VERSION 5.7 ;
BUSBITCHARS "[]" ;
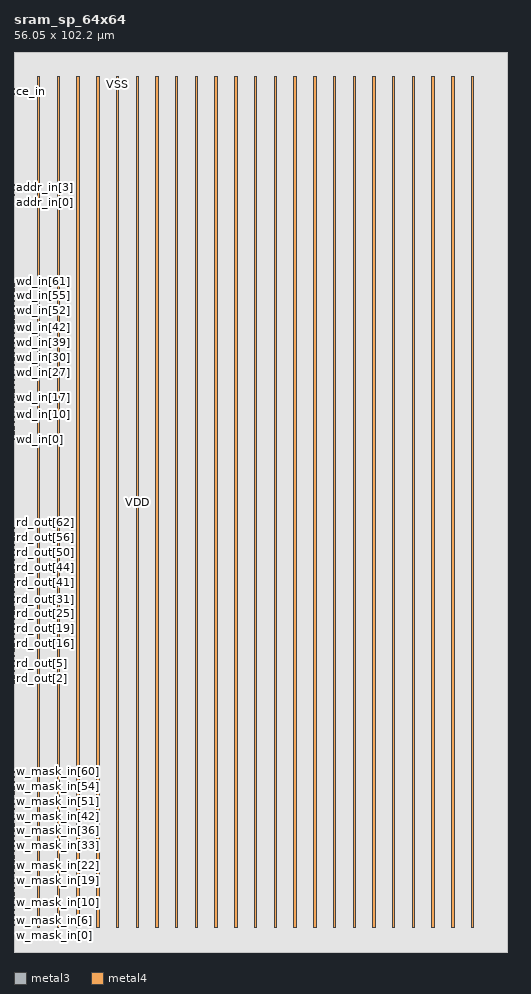
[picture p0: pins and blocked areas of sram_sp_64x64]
MACRO sram_sp_64x64
  FOREIGN sram_sp_64x64 0 0 ;
  SYMMETRY X Y R90 ;
  SIZE 56.050 BY 102.200 ;
  CLASS BLOCK ;
  PIN w_mask_in[0]
    DIRECTION INPUT ;
    USE SIGNAL ;
    SHAPE ABUTMENT ;
    PORT
      LAYER metal3 ;
      RECT 0.000 2.765 0.070 2.835 ;
    END
  END w_mask_in[0]
  PIN w_mask_in[1]
    DIRECTION INPUT ;
    USE SIGNAL ;
    SHAPE ABUTMENT ;
    PORT
      LAYER metal3 ;
      RECT 0.000 3.045 0.070 3.115 ;
    END
  END w_mask_in[1]
  PIN w_mask_in[2]
    DIRECTION INPUT ;
    USE SIGNAL ;
    SHAPE ABUTMENT ;
    PORT
      LAYER metal3 ;
      RECT 0.000 3.325 0.070 3.395 ;
    END
  END w_mask_in[2]
  PIN w_mask_in[3]
    DIRECTION INPUT ;
    USE SIGNAL ;
    SHAPE ABUTMENT ;
    PORT
      LAYER metal3 ;
      RECT 0.000 3.605 0.070 3.675 ;
    END
  END w_mask_in[3]
  PIN w_mask_in[4]
    DIRECTION INPUT ;
    USE SIGNAL ;
    SHAPE ABUTMENT ;
    PORT
      LAYER metal3 ;
      RECT 0.000 3.885 0.070 3.955 ;
    END
  END w_mask_in[4]
  PIN w_mask_in[5]
    DIRECTION INPUT ;
    USE SIGNAL ;
    SHAPE ABUTMENT ;
    PORT
      LAYER metal3 ;
      RECT 0.000 4.165 0.070 4.235 ;
    END
  END w_mask_in[5]
  PIN w_mask_in[6]
    DIRECTION INPUT ;
    USE SIGNAL ;
    SHAPE ABUTMENT ;
    PORT
      LAYER metal3 ;
      RECT 0.000 4.445 0.070 4.515 ;
    END
  END w_mask_in[6]
  PIN w_mask_in[7]
    DIRECTION INPUT ;
    USE SIGNAL ;
    SHAPE ABUTMENT ;
    PORT
      LAYER metal3 ;
      RECT 0.000 4.725 0.070 4.795 ;
    END
  END w_mask_in[7]
  PIN w_mask_in[8]
    DIRECTION INPUT ;
    USE SIGNAL ;
    SHAPE ABUTMENT ;
    PORT
      LAYER metal3 ;
      RECT 0.000 5.005 0.070 5.075 ;
    END
  END w_mask_in[8]
  PIN w_mask_in[9]
    DIRECTION INPUT ;
    USE SIGNAL ;
    SHAPE ABUTMENT ;
    PORT
      LAYER metal3 ;
      RECT 0.000 5.285 0.070 5.355 ;
    END
  END w_mask_in[9]
  PIN w_mask_in[10]
    DIRECTION INPUT ;
    USE SIGNAL ;
    SHAPE ABUTMENT ;
    PORT
      LAYER metal3 ;
      RECT 0.000 5.565 0.070 5.635 ;
    END
  END w_mask_in[10]
  PIN w_mask_in[11]
    DIRECTION INPUT ;
    USE SIGNAL ;
    SHAPE ABUTMENT ;
    PORT
      LAYER metal3 ;
      RECT 0.000 5.845 0.070 5.915 ;
    END
  END w_mask_in[11]
  PIN w_mask_in[12]
    DIRECTION INPUT ;
    USE SIGNAL ;
    SHAPE ABUTMENT ;
    PORT
      LAYER metal3 ;
      RECT 0.000 6.125 0.070 6.195 ;
    END
  END w_mask_in[12]
  PIN w_mask_in[13]
    DIRECTION INPUT ;
    USE SIGNAL ;
    SHAPE ABUTMENT ;
    PORT
      LAYER metal3 ;
      RECT 0.000 6.405 0.070 6.475 ;
    END
  END w_mask_in[13]
  PIN w_mask_in[14]
    DIRECTION INPUT ;
    USE SIGNAL ;
    SHAPE ABUTMENT ;
    PORT
      LAYER metal3 ;
      RECT 0.000 6.685 0.070 6.755 ;
    END
  END w_mask_in[14]
  PIN w_mask_in[15]
    DIRECTION INPUT ;
    USE SIGNAL ;
    SHAPE ABUTMENT ;
    PORT
      LAYER metal3 ;
      RECT 0.000 6.965 0.070 7.035 ;
    END
  END w_mask_in[15]
  PIN w_mask_in[16]
    DIRECTION INPUT ;
    USE SIGNAL ;
    SHAPE ABUTMENT ;
    PORT
      LAYER metal3 ;
      RECT 0.000 7.245 0.070 7.315 ;
    END
  END w_mask_in[16]
  PIN w_mask_in[17]
    DIRECTION INPUT ;
    USE SIGNAL ;
    SHAPE ABUTMENT ;
    PORT
      LAYER metal3 ;
      RECT 0.000 7.525 0.070 7.595 ;
    END
  END w_mask_in[17]
  PIN w_mask_in[18]
    DIRECTION INPUT ;
    USE SIGNAL ;
    SHAPE ABUTMENT ;
    PORT
      LAYER metal3 ;
      RECT 0.000 7.805 0.070 7.875 ;
    END
  END w_mask_in[18]
  PIN w_mask_in[19]
    DIRECTION INPUT ;
    USE SIGNAL ;
    SHAPE ABUTMENT ;
    PORT
      LAYER metal3 ;
      RECT 0.000 8.085 0.070 8.155 ;
    END
  END w_mask_in[19]
  PIN w_mask_in[20]
    DIRECTION INPUT ;
    USE SIGNAL ;
    SHAPE ABUTMENT ;
    PORT
      LAYER metal3 ;
      RECT 0.000 8.365 0.070 8.435 ;
    END
  END w_mask_in[20]
  PIN w_mask_in[21]
    DIRECTION INPUT ;
    USE SIGNAL ;
    SHAPE ABUTMENT ;
    PORT
      LAYER metal3 ;
      RECT 0.000 8.645 0.070 8.715 ;
    END
  END w_mask_in[21]
  PIN w_mask_in[22]
    DIRECTION INPUT ;
    USE SIGNAL ;
    SHAPE ABUTMENT ;
    PORT
      LAYER metal3 ;
      RECT 0.000 8.925 0.070 8.995 ;
    END
  END w_mask_in[22]
  PIN w_mask_in[23]
    DIRECTION INPUT ;
    USE SIGNAL ;
    SHAPE ABUTMENT ;
    PORT
      LAYER metal3 ;
      RECT 0.000 9.205 0.070 9.275 ;
    END
  END w_mask_in[23]
  PIN w_mask_in[24]
    DIRECTION INPUT ;
    USE SIGNAL ;
    SHAPE ABUTMENT ;
    PORT
      LAYER metal3 ;
      RECT 0.000 9.485 0.070 9.555 ;
    END
  END w_mask_in[24]
  PIN w_mask_in[25]
    DIRECTION INPUT ;
    USE SIGNAL ;
    SHAPE ABUTMENT ;
    PORT
      LAYER metal3 ;
      RECT 0.000 9.765 0.070 9.835 ;
    END
  END w_mask_in[25]
  PIN w_mask_in[26]
    DIRECTION INPUT ;
    USE SIGNAL ;
    SHAPE ABUTMENT ;
    PORT
      LAYER metal3 ;
      RECT 0.000 10.045 0.070 10.115 ;
    END
  END w_mask_in[26]
  PIN w_mask_in[27]
    DIRECTION INPUT ;
    USE SIGNAL ;
    SHAPE ABUTMENT ;
    PORT
      LAYER metal3 ;
      RECT 0.000 10.325 0.070 10.395 ;
    END
  END w_mask_in[27]
  PIN w_mask_in[28]
    DIRECTION INPUT ;
    USE SIGNAL ;
    SHAPE ABUTMENT ;
    PORT
      LAYER metal3 ;
      RECT 0.000 10.605 0.070 10.675 ;
    END
  END w_mask_in[28]
  PIN w_mask_in[29]
    DIRECTION INPUT ;
    USE SIGNAL ;
    SHAPE ABUTMENT ;
    PORT
      LAYER metal3 ;
      RECT 0.000 10.885 0.070 10.955 ;
    END
  END w_mask_in[29]
  PIN w_mask_in[30]
    DIRECTION INPUT ;
    USE SIGNAL ;
    SHAPE ABUTMENT ;
    PORT
      LAYER metal3 ;
      RECT 0.000 11.165 0.070 11.235 ;
    END
  END w_mask_in[30]
  PIN w_mask_in[31]
    DIRECTION INPUT ;
    USE SIGNAL ;
    SHAPE ABUTMENT ;
    PORT
      LAYER metal3 ;
      RECT 0.000 11.445 0.070 11.515 ;
    END
  END w_mask_in[31]
  PIN w_mask_in[32]
    DIRECTION INPUT ;
    USE SIGNAL ;
    SHAPE ABUTMENT ;
    PORT
      LAYER metal3 ;
      RECT 0.000 11.725 0.070 11.795 ;
    END
  END w_mask_in[32]
  PIN w_mask_in[33]
    DIRECTION INPUT ;
    USE SIGNAL ;
    SHAPE ABUTMENT ;
    PORT
      LAYER metal3 ;
      RECT 0.000 12.005 0.070 12.075 ;
    END
  END w_mask_in[33]
  PIN w_mask_in[34]
    DIRECTION INPUT ;
    USE SIGNAL ;
    SHAPE ABUTMENT ;
    PORT
      LAYER metal3 ;
      RECT 0.000 12.285 0.070 12.355 ;
    END
  END w_mask_in[34]
  PIN w_mask_in[35]
    DIRECTION INPUT ;
    USE SIGNAL ;
    SHAPE ABUTMENT ;
    PORT
      LAYER metal3 ;
      RECT 0.000 12.565 0.070 12.635 ;
    END
  END w_mask_in[35]
  PIN w_mask_in[36]
    DIRECTION INPUT ;
    USE SIGNAL ;
    SHAPE ABUTMENT ;
    PORT
      LAYER metal3 ;
      RECT 0.000 12.845 0.070 12.915 ;
    END
  END w_mask_in[36]
  PIN w_mask_in[37]
    DIRECTION INPUT ;
    USE SIGNAL ;
    SHAPE ABUTMENT ;
    PORT
      LAYER metal3 ;
      RECT 0.000 13.125 0.070 13.195 ;
    END
  END w_mask_in[37]
  PIN w_mask_in[38]
    DIRECTION INPUT ;
    USE SIGNAL ;
    SHAPE ABUTMENT ;
    PORT
      LAYER metal3 ;
      RECT 0.000 13.405 0.070 13.475 ;
    END
  END w_mask_in[38]
  PIN w_mask_in[39]
    DIRECTION INPUT ;
    USE SIGNAL ;
    SHAPE ABUTMENT ;
    PORT
      LAYER metal3 ;
      RECT 0.000 13.685 0.070 13.755 ;
    END
  END w_mask_in[39]
  PIN w_mask_in[40]
    DIRECTION INPUT ;
    USE SIGNAL ;
    SHAPE ABUTMENT ;
    PORT
      LAYER metal3 ;
      RECT 0.000 13.965 0.070 14.035 ;
    END
  END w_mask_in[40]
  PIN w_mask_in[41]
    DIRECTION INPUT ;
    USE SIGNAL ;
    SHAPE ABUTMENT ;
    PORT
      LAYER metal3 ;
      RECT 0.000 14.245 0.070 14.315 ;
    END
  END w_mask_in[41]
  PIN w_mask_in[42]
    DIRECTION INPUT ;
    USE SIGNAL ;
    SHAPE ABUTMENT ;
    PORT
      LAYER metal3 ;
      RECT 0.000 14.525 0.070 14.595 ;
    END
  END w_mask_in[42]
  PIN w_mask_in[43]
    DIRECTION INPUT ;
    USE SIGNAL ;
    SHAPE ABUTMENT ;
    PORT
      LAYER metal3 ;
      RECT 0.000 14.805 0.070 14.875 ;
    END
  END w_mask_in[43]
  PIN w_mask_in[44]
    DIRECTION INPUT ;
    USE SIGNAL ;
    SHAPE ABUTMENT ;
    PORT
      LAYER metal3 ;
      RECT 0.000 15.085 0.070 15.155 ;
    END
  END w_mask_in[44]
  PIN w_mask_in[45]
    DIRECTION INPUT ;
    USE SIGNAL ;
    SHAPE ABUTMENT ;
    PORT
      LAYER metal3 ;
      RECT 0.000 15.365 0.070 15.435 ;
    END
  END w_mask_in[45]
  PIN w_mask_in[46]
    DIRECTION INPUT ;
    USE SIGNAL ;
    SHAPE ABUTMENT ;
    PORT
      LAYER metal3 ;
      RECT 0.000 15.645 0.070 15.715 ;
    END
  END w_mask_in[46]
  PIN w_mask_in[47]
    DIRECTION INPUT ;
    USE SIGNAL ;
    SHAPE ABUTMENT ;
    PORT
      LAYER metal3 ;
      RECT 0.000 15.925 0.070 15.995 ;
    END
  END w_mask_in[47]
  PIN w_mask_in[48]
    DIRECTION INPUT ;
    USE SIGNAL ;
    SHAPE ABUTMENT ;
    PORT
      LAYER metal3 ;
      RECT 0.000 16.205 0.070 16.275 ;
    END
  END w_mask_in[48]
  PIN w_mask_in[49]
    DIRECTION INPUT ;
    USE SIGNAL ;
    SHAPE ABUTMENT ;
    PORT
      LAYER metal3 ;
      RECT 0.000 16.485 0.070 16.555 ;
    END
  END w_mask_in[49]
  PIN w_mask_in[50]
    DIRECTION INPUT ;
    USE SIGNAL ;
    SHAPE ABUTMENT ;
    PORT
      LAYER metal3 ;
      RECT 0.000 16.765 0.070 16.835 ;
    END
  END w_mask_in[50]
  PIN w_mask_in[51]
    DIRECTION INPUT ;
    USE SIGNAL ;
    SHAPE ABUTMENT ;
    PORT
      LAYER metal3 ;
      RECT 0.000 17.045 0.070 17.115 ;
    END
  END w_mask_in[51]
  PIN w_mask_in[52]
    DIRECTION INPUT ;
    USE SIGNAL ;
    SHAPE ABUTMENT ;
    PORT
      LAYER metal3 ;
      RECT 0.000 17.325 0.070 17.395 ;
    END
  END w_mask_in[52]
  PIN w_mask_in[53]
    DIRECTION INPUT ;
    USE SIGNAL ;
    SHAPE ABUTMENT ;
    PORT
      LAYER metal3 ;
      RECT 0.000 17.605 0.070 17.675 ;
    END
  END w_mask_in[53]
  PIN w_mask_in[54]
    DIRECTION INPUT ;
    USE SIGNAL ;
    SHAPE ABUTMENT ;
    PORT
      LAYER metal3 ;
      RECT 0.000 17.885 0.070 17.955 ;
    END
  END w_mask_in[54]
  PIN w_mask_in[55]
    DIRECTION INPUT ;
    USE SIGNAL ;
    SHAPE ABUTMENT ;
    PORT
      LAYER metal3 ;
      RECT 0.000 18.165 0.070 18.235 ;
    END
  END w_mask_in[55]
  PIN w_mask_in[56]
    DIRECTION INPUT ;
    USE SIGNAL ;
    SHAPE ABUTMENT ;
    PORT
      LAYER metal3 ;
      RECT 0.000 18.445 0.070 18.515 ;
    END
  END w_mask_in[56]
  PIN w_mask_in[57]
    DIRECTION INPUT ;
    USE SIGNAL ;
    SHAPE ABUTMENT ;
    PORT
      LAYER metal3 ;
      RECT 0.000 18.725 0.070 18.795 ;
    END
  END w_mask_in[57]
  PIN w_mask_in[58]
    DIRECTION INPUT ;
    USE SIGNAL ;
    SHAPE ABUTMENT ;
    PORT
      LAYER metal3 ;
      RECT 0.000 19.005 0.070 19.075 ;
    END
  END w_mask_in[58]
  PIN w_mask_in[59]
    DIRECTION INPUT ;
    USE SIGNAL ;
    SHAPE ABUTMENT ;
    PORT
      LAYER metal3 ;
      RECT 0.000 19.285 0.070 19.355 ;
    END
  END w_mask_in[59]
  PIN w_mask_in[60]
    DIRECTION INPUT ;
    USE SIGNAL ;
    SHAPE ABUTMENT ;
    PORT
      LAYER metal3 ;
      RECT 0.000 19.565 0.070 19.635 ;
    END
  END w_mask_in[60]
  PIN w_mask_in[61]
    DIRECTION INPUT ;
    USE SIGNAL ;
    SHAPE ABUTMENT ;
    PORT
      LAYER metal3 ;
      RECT 0.000 19.845 0.070 19.915 ;
    END
  END w_mask_in[61]
  PIN w_mask_in[62]
    DIRECTION INPUT ;
    USE SIGNAL ;
    SHAPE ABUTMENT ;
    PORT
      LAYER metal3 ;
      RECT 0.000 20.125 0.070 20.195 ;
    END
  END w_mask_in[62]
  PIN w_mask_in[63]
    DIRECTION INPUT ;
    USE SIGNAL ;
    SHAPE ABUTMENT ;
    PORT
      LAYER metal3 ;
      RECT 0.000 20.405 0.070 20.475 ;
    END
  END w_mask_in[63]
  PIN rd_out[0]
    DIRECTION OUTPUT ;
    USE SIGNAL ;
    SHAPE ABUTMENT ;
    PORT
      LAYER metal3 ;
      RECT 0.000 30.485 0.070 30.555 ;
    END
  END rd_out[0]
  PIN rd_out[1]
    DIRECTION OUTPUT ;
    USE SIGNAL ;
    SHAPE ABUTMENT ;
    PORT
      LAYER metal3 ;
      RECT 0.000 30.765 0.070 30.835 ;
    END
  END rd_out[1]
  PIN rd_out[2]
    DIRECTION OUTPUT ;
    USE SIGNAL ;
    SHAPE ABUTMENT ;
    PORT
      LAYER metal3 ;
      RECT 0.000 31.045 0.070 31.115 ;
    END
  END rd_out[2]
  PIN rd_out[3]
    DIRECTION OUTPUT ;
    USE SIGNAL ;
    SHAPE ABUTMENT ;
    PORT
      LAYER metal3 ;
      RECT 0.000 31.325 0.070 31.395 ;
    END
  END rd_out[3]
  PIN rd_out[4]
    DIRECTION OUTPUT ;
    USE SIGNAL ;
    SHAPE ABUTMENT ;
    PORT
      LAYER metal3 ;
      RECT 0.000 31.605 0.070 31.675 ;
    END
  END rd_out[4]
  PIN rd_out[5]
    DIRECTION OUTPUT ;
    USE SIGNAL ;
    SHAPE ABUTMENT ;
    PORT
      LAYER metal3 ;
      RECT 0.000 31.885 0.070 31.955 ;
    END
  END rd_out[5]
  PIN rd_out[6]
    DIRECTION OUTPUT ;
    USE SIGNAL ;
    SHAPE ABUTMENT ;
    PORT
      LAYER metal3 ;
      RECT 0.000 32.165 0.070 32.235 ;
    END
  END rd_out[6]
  PIN rd_out[7]
    DIRECTION OUTPUT ;
    USE SIGNAL ;
    SHAPE ABUTMENT ;
    PORT
      LAYER metal3 ;
      RECT 0.000 32.445 0.070 32.515 ;
    END
  END rd_out[7]
  PIN rd_out[8]
    DIRECTION OUTPUT ;
    USE SIGNAL ;
    SHAPE ABUTMENT ;
    PORT
      LAYER metal3 ;
      RECT 0.000 32.725 0.070 32.795 ;
    END
  END rd_out[8]
  PIN rd_out[9]
    DIRECTION OUTPUT ;
    USE SIGNAL ;
    SHAPE ABUTMENT ;
    PORT
      LAYER metal3 ;
      RECT 0.000 33.005 0.070 33.075 ;
    END
  END rd_out[9]
  PIN rd_out[10]
    DIRECTION OUTPUT ;
    USE SIGNAL ;
    SHAPE ABUTMENT ;
    PORT
      LAYER metal3 ;
      RECT 0.000 33.285 0.070 33.355 ;
    END
  END rd_out[10]
  PIN rd_out[11]
    DIRECTION OUTPUT ;
    USE SIGNAL ;
    SHAPE ABUTMENT ;
    PORT
      LAYER metal3 ;
      RECT 0.000 33.565 0.070 33.635 ;
    END
  END rd_out[11]
  PIN rd_out[12]
    DIRECTION OUTPUT ;
    USE SIGNAL ;
    SHAPE ABUTMENT ;
    PORT
      LAYER metal3 ;
      RECT 0.000 33.845 0.070 33.915 ;
    END
  END rd_out[12]
  PIN rd_out[13]
    DIRECTION OUTPUT ;
    USE SIGNAL ;
    SHAPE ABUTMENT ;
    PORT
      LAYER metal3 ;
      RECT 0.000 34.125 0.070 34.195 ;
    END
  END rd_out[13]
  PIN rd_out[14]
    DIRECTION OUTPUT ;
    USE SIGNAL ;
    SHAPE ABUTMENT ;
    PORT
      LAYER metal3 ;
      RECT 0.000 34.405 0.070 34.475 ;
    END
  END rd_out[14]
  PIN rd_out[15]
    DIRECTION OUTPUT ;
    USE SIGNAL ;
    SHAPE ABUTMENT ;
    PORT
      LAYER metal3 ;
      RECT 0.000 34.685 0.070 34.755 ;
    END
  END rd_out[15]
  PIN rd_out[16]
    DIRECTION OUTPUT ;
    USE SIGNAL ;
    SHAPE ABUTMENT ;
    PORT
      LAYER metal3 ;
      RECT 0.000 34.965 0.070 35.035 ;
    END
  END rd_out[16]
  PIN rd_out[17]
    DIRECTION OUTPUT ;
    USE SIGNAL ;
    SHAPE ABUTMENT ;
    PORT
      LAYER metal3 ;
      RECT 0.000 35.245 0.070 35.315 ;
    END
  END rd_out[17]
  PIN rd_out[18]
    DIRECTION OUTPUT ;
    USE SIGNAL ;
    SHAPE ABUTMENT ;
    PORT
      LAYER metal3 ;
      RECT 0.000 35.525 0.070 35.595 ;
    END
  END rd_out[18]
  PIN rd_out[19]
    DIRECTION OUTPUT ;
    USE SIGNAL ;
    SHAPE ABUTMENT ;
    PORT
      LAYER metal3 ;
      RECT 0.000 35.805 0.070 35.875 ;
    END
  END rd_out[19]
  PIN rd_out[20]
    DIRECTION OUTPUT ;
    USE SIGNAL ;
    SHAPE ABUTMENT ;
    PORT
      LAYER metal3 ;
      RECT 0.000 36.085 0.070 36.155 ;
    END
  END rd_out[20]
  PIN rd_out[21]
    DIRECTION OUTPUT ;
    USE SIGNAL ;
    SHAPE ABUTMENT ;
    PORT
      LAYER metal3 ;
      RECT 0.000 36.365 0.070 36.435 ;
    END
  END rd_out[21]
  PIN rd_out[22]
    DIRECTION OUTPUT ;
    USE SIGNAL ;
    SHAPE ABUTMENT ;
    PORT
      LAYER metal3 ;
      RECT 0.000 36.645 0.070 36.715 ;
    END
  END rd_out[22]
  PIN rd_out[23]
    DIRECTION OUTPUT ;
    USE SIGNAL ;
    SHAPE ABUTMENT ;
    PORT
      LAYER metal3 ;
      RECT 0.000 36.925 0.070 36.995 ;
    END
  END rd_out[23]
  PIN rd_out[24]
    DIRECTION OUTPUT ;
    USE SIGNAL ;
    SHAPE ABUTMENT ;
    PORT
      LAYER metal3 ;
      RECT 0.000 37.205 0.070 37.275 ;
    END
  END rd_out[24]
  PIN rd_out[25]
    DIRECTION OUTPUT ;
    USE SIGNAL ;
    SHAPE ABUTMENT ;
    PORT
      LAYER metal3 ;
      RECT 0.000 37.485 0.070 37.555 ;
    END
  END rd_out[25]
  PIN rd_out[26]
    DIRECTION OUTPUT ;
    USE SIGNAL ;
    SHAPE ABUTMENT ;
    PORT
      LAYER metal3 ;
      RECT 0.000 37.765 0.070 37.835 ;
    END
  END rd_out[26]
  PIN rd_out[27]
    DIRECTION OUTPUT ;
    USE SIGNAL ;
    SHAPE ABUTMENT ;
    PORT
      LAYER metal3 ;
      RECT 0.000 38.045 0.070 38.115 ;
    END
  END rd_out[27]
  PIN rd_out[28]
    DIRECTION OUTPUT ;
    USE SIGNAL ;
    SHAPE ABUTMENT ;
    PORT
      LAYER metal3 ;
      RECT 0.000 38.325 0.070 38.395 ;
    END
  END rd_out[28]
  PIN rd_out[29]
    DIRECTION OUTPUT ;
    USE SIGNAL ;
    SHAPE ABUTMENT ;
    PORT
      LAYER metal3 ;
      RECT 0.000 38.605 0.070 38.675 ;
    END
  END rd_out[29]
  PIN rd_out[30]
    DIRECTION OUTPUT ;
    USE SIGNAL ;
    SHAPE ABUTMENT ;
    PORT
      LAYER metal3 ;
      RECT 0.000 38.885 0.070 38.955 ;
    END
  END rd_out[30]
  PIN rd_out[31]
    DIRECTION OUTPUT ;
    USE SIGNAL ;
    SHAPE ABUTMENT ;
    PORT
      LAYER metal3 ;
      RECT 0.000 39.165 0.070 39.235 ;
    END
  END rd_out[31]
  PIN rd_out[32]
    DIRECTION OUTPUT ;
    USE SIGNAL ;
    SHAPE ABUTMENT ;
    PORT
      LAYER metal3 ;
      RECT 0.000 39.445 0.070 39.515 ;
    END
  END rd_out[32]
  PIN rd_out[33]
    DIRECTION OUTPUT ;
    USE SIGNAL ;
    SHAPE ABUTMENT ;
    PORT
      LAYER metal3 ;
      RECT 0.000 39.725 0.070 39.795 ;
    END
  END rd_out[33]
  PIN rd_out[34]
    DIRECTION OUTPUT ;
    USE SIGNAL ;
    SHAPE ABUTMENT ;
    PORT
      LAYER metal3 ;
      RECT 0.000 40.005 0.070 40.075 ;
    END
  END rd_out[34]
  PIN rd_out[35]
    DIRECTION OUTPUT ;
    USE SIGNAL ;
    SHAPE ABUTMENT ;
    PORT
      LAYER metal3 ;
      RECT 0.000 40.285 0.070 40.355 ;
    END
  END rd_out[35]
  PIN rd_out[36]
    DIRECTION OUTPUT ;
    USE SIGNAL ;
    SHAPE ABUTMENT ;
    PORT
      LAYER metal3 ;
      RECT 0.000 40.565 0.070 40.635 ;
    END
  END rd_out[36]
  PIN rd_out[37]
    DIRECTION OUTPUT ;
    USE SIGNAL ;
    SHAPE ABUTMENT ;
    PORT
      LAYER metal3 ;
      RECT 0.000 40.845 0.070 40.915 ;
    END
  END rd_out[37]
  PIN rd_out[38]
    DIRECTION OUTPUT ;
    USE SIGNAL ;
    SHAPE ABUTMENT ;
    PORT
      LAYER metal3 ;
      RECT 0.000 41.125 0.070 41.195 ;
    END
  END rd_out[38]
  PIN rd_out[39]
    DIRECTION OUTPUT ;
    USE SIGNAL ;
    SHAPE ABUTMENT ;
    PORT
      LAYER metal3 ;
      RECT 0.000 41.405 0.070 41.475 ;
    END
  END rd_out[39]
  PIN rd_out[40]
    DIRECTION OUTPUT ;
    USE SIGNAL ;
    SHAPE ABUTMENT ;
    PORT
      LAYER metal3 ;
      RECT 0.000 41.685 0.070 41.755 ;
    END
  END rd_out[40]
  PIN rd_out[41]
    DIRECTION OUTPUT ;
    USE SIGNAL ;
    SHAPE ABUTMENT ;
    PORT
      LAYER metal3 ;
      RECT 0.000 41.965 0.070 42.035 ;
    END
  END rd_out[41]
  PIN rd_out[42]
    DIRECTION OUTPUT ;
    USE SIGNAL ;
    SHAPE ABUTMENT ;
    PORT
      LAYER metal3 ;
      RECT 0.000 42.245 0.070 42.315 ;
    END
  END rd_out[42]
  PIN rd_out[43]
    DIRECTION OUTPUT ;
    USE SIGNAL ;
    SHAPE ABUTMENT ;
    PORT
      LAYER metal3 ;
      RECT 0.000 42.525 0.070 42.595 ;
    END
  END rd_out[43]
  PIN rd_out[44]
    DIRECTION OUTPUT ;
    USE SIGNAL ;
    SHAPE ABUTMENT ;
    PORT
      LAYER metal3 ;
      RECT 0.000 42.805 0.070 42.875 ;
    END
  END rd_out[44]
  PIN rd_out[45]
    DIRECTION OUTPUT ;
    USE SIGNAL ;
    SHAPE ABUTMENT ;
    PORT
      LAYER metal3 ;
      RECT 0.000 43.085 0.070 43.155 ;
    END
  END rd_out[45]
  PIN rd_out[46]
    DIRECTION OUTPUT ;
    USE SIGNAL ;
    SHAPE ABUTMENT ;
    PORT
      LAYER metal3 ;
      RECT 0.000 43.365 0.070 43.435 ;
    END
  END rd_out[46]
  PIN rd_out[47]
    DIRECTION OUTPUT ;
    USE SIGNAL ;
    SHAPE ABUTMENT ;
    PORT
      LAYER metal3 ;
      RECT 0.000 43.645 0.070 43.715 ;
    END
  END rd_out[47]
  PIN rd_out[48]
    DIRECTION OUTPUT ;
    USE SIGNAL ;
    SHAPE ABUTMENT ;
    PORT
      LAYER metal3 ;
      RECT 0.000 43.925 0.070 43.995 ;
    END
  END rd_out[48]
  PIN rd_out[49]
    DIRECTION OUTPUT ;
    USE SIGNAL ;
    SHAPE ABUTMENT ;
    PORT
      LAYER metal3 ;
      RECT 0.000 44.205 0.070 44.275 ;
    END
  END rd_out[49]
  PIN rd_out[50]
    DIRECTION OUTPUT ;
    USE SIGNAL ;
    SHAPE ABUTMENT ;
    PORT
      LAYER metal3 ;
      RECT 0.000 44.485 0.070 44.555 ;
    END
  END rd_out[50]
  PIN rd_out[51]
    DIRECTION OUTPUT ;
    USE SIGNAL ;
    SHAPE ABUTMENT ;
    PORT
      LAYER metal3 ;
      RECT 0.000 44.765 0.070 44.835 ;
    END
  END rd_out[51]
  PIN rd_out[52]
    DIRECTION OUTPUT ;
    USE SIGNAL ;
    SHAPE ABUTMENT ;
    PORT
      LAYER metal3 ;
      RECT 0.000 45.045 0.070 45.115 ;
    END
  END rd_out[52]
  PIN rd_out[53]
    DIRECTION OUTPUT ;
    USE SIGNAL ;
    SHAPE ABUTMENT ;
    PORT
      LAYER metal3 ;
      RECT 0.000 45.325 0.070 45.395 ;
    END
  END rd_out[53]
  PIN rd_out[54]
    DIRECTION OUTPUT ;
    USE SIGNAL ;
    SHAPE ABUTMENT ;
    PORT
      LAYER metal3 ;
      RECT 0.000 45.605 0.070 45.675 ;
    END
  END rd_out[54]
  PIN rd_out[55]
    DIRECTION OUTPUT ;
    USE SIGNAL ;
    SHAPE ABUTMENT ;
    PORT
      LAYER metal3 ;
      RECT 0.000 45.885 0.070 45.955 ;
    END
  END rd_out[55]
  PIN rd_out[56]
    DIRECTION OUTPUT ;
    USE SIGNAL ;
    SHAPE ABUTMENT ;
    PORT
      LAYER metal3 ;
      RECT 0.000 46.165 0.070 46.235 ;
    END
  END rd_out[56]
  PIN rd_out[57]
    DIRECTION OUTPUT ;
    USE SIGNAL ;
    SHAPE ABUTMENT ;
    PORT
      LAYER metal3 ;
      RECT 0.000 46.445 0.070 46.515 ;
    END
  END rd_out[57]
  PIN rd_out[58]
    DIRECTION OUTPUT ;
    USE SIGNAL ;
    SHAPE ABUTMENT ;
    PORT
      LAYER metal3 ;
      RECT 0.000 46.725 0.070 46.795 ;
    END
  END rd_out[58]
  PIN rd_out[59]
    DIRECTION OUTPUT ;
    USE SIGNAL ;
    SHAPE ABUTMENT ;
    PORT
      LAYER metal3 ;
      RECT 0.000 47.005 0.070 47.075 ;
    END
  END rd_out[59]
  PIN rd_out[60]
    DIRECTION OUTPUT ;
    USE SIGNAL ;
    SHAPE ABUTMENT ;
    PORT
      LAYER metal3 ;
      RECT 0.000 47.285 0.070 47.355 ;
    END
  END rd_out[60]
  PIN rd_out[61]
    DIRECTION OUTPUT ;
    USE SIGNAL ;
    SHAPE ABUTMENT ;
    PORT
      LAYER metal3 ;
      RECT 0.000 47.565 0.070 47.635 ;
    END
  END rd_out[61]
  PIN rd_out[62]
    DIRECTION OUTPUT ;
    USE SIGNAL ;
    SHAPE ABUTMENT ;
    PORT
      LAYER metal3 ;
      RECT 0.000 47.845 0.070 47.915 ;
    END
  END rd_out[62]
  PIN rd_out[63]
    DIRECTION OUTPUT ;
    USE SIGNAL ;
    SHAPE ABUTMENT ;
    PORT
      LAYER metal3 ;
      RECT 0.000 48.125 0.070 48.195 ;
    END
  END rd_out[63]
  PIN wd_in[0]
    DIRECTION INPUT ;
    USE SIGNAL ;
    SHAPE ABUTMENT ;
    PORT
      LAYER metal3 ;
      RECT 0.000 58.205 0.070 58.275 ;
    END
  END wd_in[0]
  PIN wd_in[1]
    DIRECTION INPUT ;
    USE SIGNAL ;
    SHAPE ABUTMENT ;
    PORT
      LAYER metal3 ;
      RECT 0.000 58.485 0.070 58.555 ;
    END
  END wd_in[1]
  PIN wd_in[2]
    DIRECTION INPUT ;
    USE SIGNAL ;
    SHAPE ABUTMENT ;
    PORT
      LAYER metal3 ;
      RECT 0.000 58.765 0.070 58.835 ;
    END
  END wd_in[2]
  PIN wd_in[3]
    DIRECTION INPUT ;
    USE SIGNAL ;
    SHAPE ABUTMENT ;
    PORT
      LAYER metal3 ;
      RECT 0.000 59.045 0.070 59.115 ;
    END
  END wd_in[3]
  PIN wd_in[4]
    DIRECTION INPUT ;
    USE SIGNAL ;
    SHAPE ABUTMENT ;
    PORT
      LAYER metal3 ;
      RECT 0.000 59.325 0.070 59.395 ;
    END
  END wd_in[4]
  PIN wd_in[5]
    DIRECTION INPUT ;
    USE SIGNAL ;
    SHAPE ABUTMENT ;
    PORT
      LAYER metal3 ;
      RECT 0.000 59.605 0.070 59.675 ;
    END
  END wd_in[5]
  PIN wd_in[6]
    DIRECTION INPUT ;
    USE SIGNAL ;
    SHAPE ABUTMENT ;
    PORT
      LAYER metal3 ;
      RECT 0.000 59.885 0.070 59.955 ;
    END
  END wd_in[6]
  PIN wd_in[7]
    DIRECTION INPUT ;
    USE SIGNAL ;
    SHAPE ABUTMENT ;
    PORT
      LAYER metal3 ;
      RECT 0.000 60.165 0.070 60.235 ;
    END
  END wd_in[7]
  PIN wd_in[8]
    DIRECTION INPUT ;
    USE SIGNAL ;
    SHAPE ABUTMENT ;
    PORT
      LAYER metal3 ;
      RECT 0.000 60.445 0.070 60.515 ;
    END
  END wd_in[8]
  PIN wd_in[9]
    DIRECTION INPUT ;
    USE SIGNAL ;
    SHAPE ABUTMENT ;
    PORT
      LAYER metal3 ;
      RECT 0.000 60.725 0.070 60.795 ;
    END
  END wd_in[9]
  PIN wd_in[10]
    DIRECTION INPUT ;
    USE SIGNAL ;
    SHAPE ABUTMENT ;
    PORT
      LAYER metal3 ;
      RECT 0.000 61.005 0.070 61.075 ;
    END
  END wd_in[10]
  PIN wd_in[11]
    DIRECTION INPUT ;
    USE SIGNAL ;
    SHAPE ABUTMENT ;
    PORT
      LAYER metal3 ;
      RECT 0.000 61.285 0.070 61.355 ;
    END
  END wd_in[11]
  PIN wd_in[12]
    DIRECTION INPUT ;
    USE SIGNAL ;
    SHAPE ABUTMENT ;
    PORT
      LAYER metal3 ;
      RECT 0.000 61.565 0.070 61.635 ;
    END
  END wd_in[12]
  PIN wd_in[13]
    DIRECTION INPUT ;
    USE SIGNAL ;
    SHAPE ABUTMENT ;
    PORT
      LAYER metal3 ;
      RECT 0.000 61.845 0.070 61.915 ;
    END
  END wd_in[13]
  PIN wd_in[14]
    DIRECTION INPUT ;
    USE SIGNAL ;
    SHAPE ABUTMENT ;
    PORT
      LAYER metal3 ;
      RECT 0.000 62.125 0.070 62.195 ;
    END
  END wd_in[14]
  PIN wd_in[15]
    DIRECTION INPUT ;
    USE SIGNAL ;
    SHAPE ABUTMENT ;
    PORT
      LAYER metal3 ;
      RECT 0.000 62.405 0.070 62.475 ;
    END
  END wd_in[15]
  PIN wd_in[16]
    DIRECTION INPUT ;
    USE SIGNAL ;
    SHAPE ABUTMENT ;
    PORT
      LAYER metal3 ;
      RECT 0.000 62.685 0.070 62.755 ;
    END
  END wd_in[16]
  PIN wd_in[17]
    DIRECTION INPUT ;
    USE SIGNAL ;
    SHAPE ABUTMENT ;
    PORT
      LAYER metal3 ;
      RECT 0.000 62.965 0.070 63.035 ;
    END
  END wd_in[17]
  PIN wd_in[18]
    DIRECTION INPUT ;
    USE SIGNAL ;
    SHAPE ABUTMENT ;
    PORT
      LAYER metal3 ;
      RECT 0.000 63.245 0.070 63.315 ;
    END
  END wd_in[18]
  PIN wd_in[19]
    DIRECTION INPUT ;
    USE SIGNAL ;
    SHAPE ABUTMENT ;
    PORT
      LAYER metal3 ;
      RECT 0.000 63.525 0.070 63.595 ;
    END
  END wd_in[19]
  PIN wd_in[20]
    DIRECTION INPUT ;
    USE SIGNAL ;
    SHAPE ABUTMENT ;
    PORT
      LAYER metal3 ;
      RECT 0.000 63.805 0.070 63.875 ;
    END
  END wd_in[20]
  PIN wd_in[21]
    DIRECTION INPUT ;
    USE SIGNAL ;
    SHAPE ABUTMENT ;
    PORT
      LAYER metal3 ;
      RECT 0.000 64.085 0.070 64.155 ;
    END
  END wd_in[21]
  PIN wd_in[22]
    DIRECTION INPUT ;
    USE SIGNAL ;
    SHAPE ABUTMENT ;
    PORT
      LAYER metal3 ;
      RECT 0.000 64.365 0.070 64.435 ;
    END
  END wd_in[22]
  PIN wd_in[23]
    DIRECTION INPUT ;
    USE SIGNAL ;
    SHAPE ABUTMENT ;
    PORT
      LAYER metal3 ;
      RECT 0.000 64.645 0.070 64.715 ;
    END
  END wd_in[23]
  PIN wd_in[24]
    DIRECTION INPUT ;
    USE SIGNAL ;
    SHAPE ABUTMENT ;
    PORT
      LAYER metal3 ;
      RECT 0.000 64.925 0.070 64.995 ;
    END
  END wd_in[24]
  PIN wd_in[25]
    DIRECTION INPUT ;
    USE SIGNAL ;
    SHAPE ABUTMENT ;
    PORT
      LAYER metal3 ;
      RECT 0.000 65.205 0.070 65.275 ;
    END
  END wd_in[25]
  PIN wd_in[26]
    DIRECTION INPUT ;
    USE SIGNAL ;
    SHAPE ABUTMENT ;
    PORT
      LAYER metal3 ;
      RECT 0.000 65.485 0.070 65.555 ;
    END
  END wd_in[26]
  PIN wd_in[27]
    DIRECTION INPUT ;
    USE SIGNAL ;
    SHAPE ABUTMENT ;
    PORT
      LAYER metal3 ;
      RECT 0.000 65.765 0.070 65.835 ;
    END
  END wd_in[27]
  PIN wd_in[28]
    DIRECTION INPUT ;
    USE SIGNAL ;
    SHAPE ABUTMENT ;
    PORT
      LAYER metal3 ;
      RECT 0.000 66.045 0.070 66.115 ;
    END
  END wd_in[28]
  PIN wd_in[29]
    DIRECTION INPUT ;
    USE SIGNAL ;
    SHAPE ABUTMENT ;
    PORT
      LAYER metal3 ;
      RECT 0.000 66.325 0.070 66.395 ;
    END
  END wd_in[29]
  PIN wd_in[30]
    DIRECTION INPUT ;
    USE SIGNAL ;
    SHAPE ABUTMENT ;
    PORT
      LAYER metal3 ;
      RECT 0.000 66.605 0.070 66.675 ;
    END
  END wd_in[30]
  PIN wd_in[31]
    DIRECTION INPUT ;
    USE SIGNAL ;
    SHAPE ABUTMENT ;
    PORT
      LAYER metal3 ;
      RECT 0.000 66.885 0.070 66.955 ;
    END
  END wd_in[31]
  PIN wd_in[32]
    DIRECTION INPUT ;
    USE SIGNAL ;
    SHAPE ABUTMENT ;
    PORT
      LAYER metal3 ;
      RECT 0.000 67.165 0.070 67.235 ;
    END
  END wd_in[32]
  PIN wd_in[33]
    DIRECTION INPUT ;
    USE SIGNAL ;
    SHAPE ABUTMENT ;
    PORT
      LAYER metal3 ;
      RECT 0.000 67.445 0.070 67.515 ;
    END
  END wd_in[33]
  PIN wd_in[34]
    DIRECTION INPUT ;
    USE SIGNAL ;
    SHAPE ABUTMENT ;
    PORT
      LAYER metal3 ;
      RECT 0.000 67.725 0.070 67.795 ;
    END
  END wd_in[34]
  PIN wd_in[35]
    DIRECTION INPUT ;
    USE SIGNAL ;
    SHAPE ABUTMENT ;
    PORT
      LAYER metal3 ;
      RECT 0.000 68.005 0.070 68.075 ;
    END
  END wd_in[35]
  PIN wd_in[36]
    DIRECTION INPUT ;
    USE SIGNAL ;
    SHAPE ABUTMENT ;
    PORT
      LAYER metal3 ;
      RECT 0.000 68.285 0.070 68.355 ;
    END
  END wd_in[36]
  PIN wd_in[37]
    DIRECTION INPUT ;
    USE SIGNAL ;
    SHAPE ABUTMENT ;
    PORT
      LAYER metal3 ;
      RECT 0.000 68.565 0.070 68.635 ;
    END
  END wd_in[37]
  PIN wd_in[38]
    DIRECTION INPUT ;
    USE SIGNAL ;
    SHAPE ABUTMENT ;
    PORT
      LAYER metal3 ;
      RECT 0.000 68.845 0.070 68.915 ;
    END
  END wd_in[38]
  PIN wd_in[39]
    DIRECTION INPUT ;
    USE SIGNAL ;
    SHAPE ABUTMENT ;
    PORT
      LAYER metal3 ;
      RECT 0.000 69.125 0.070 69.195 ;
    END
  END wd_in[39]
  PIN wd_in[40]
    DIRECTION INPUT ;
    USE SIGNAL ;
    SHAPE ABUTMENT ;
    PORT
      LAYER metal3 ;
      RECT 0.000 69.405 0.070 69.475 ;
    END
  END wd_in[40]
  PIN wd_in[41]
    DIRECTION INPUT ;
    USE SIGNAL ;
    SHAPE ABUTMENT ;
    PORT
      LAYER metal3 ;
      RECT 0.000 69.685 0.070 69.755 ;
    END
  END wd_in[41]
  PIN wd_in[42]
    DIRECTION INPUT ;
    USE SIGNAL ;
    SHAPE ABUTMENT ;
    PORT
      LAYER metal3 ;
      RECT 0.000 69.965 0.070 70.035 ;
    END
  END wd_in[42]
  PIN wd_in[43]
    DIRECTION INPUT ;
    USE SIGNAL ;
    SHAPE ABUTMENT ;
    PORT
      LAYER metal3 ;
      RECT 0.000 70.245 0.070 70.315 ;
    END
  END wd_in[43]
  PIN wd_in[44]
    DIRECTION INPUT ;
    USE SIGNAL ;
    SHAPE ABUTMENT ;
    PORT
      LAYER metal3 ;
      RECT 0.000 70.525 0.070 70.595 ;
    END
  END wd_in[44]
  PIN wd_in[45]
    DIRECTION INPUT ;
    USE SIGNAL ;
    SHAPE ABUTMENT ;
    PORT
      LAYER metal3 ;
      RECT 0.000 70.805 0.070 70.875 ;
    END
  END wd_in[45]
  PIN wd_in[46]
    DIRECTION INPUT ;
    USE SIGNAL ;
    SHAPE ABUTMENT ;
    PORT
      LAYER metal3 ;
      RECT 0.000 71.085 0.070 71.155 ;
    END
  END wd_in[46]
  PIN wd_in[47]
    DIRECTION INPUT ;
    USE SIGNAL ;
    SHAPE ABUTMENT ;
    PORT
      LAYER metal3 ;
      RECT 0.000 71.365 0.070 71.435 ;
    END
  END wd_in[47]
  PIN wd_in[48]
    DIRECTION INPUT ;
    USE SIGNAL ;
    SHAPE ABUTMENT ;
    PORT
      LAYER metal3 ;
      RECT 0.000 71.645 0.070 71.715 ;
    END
  END wd_in[48]
  PIN wd_in[49]
    DIRECTION INPUT ;
    USE SIGNAL ;
    SHAPE ABUTMENT ;
    PORT
      LAYER metal3 ;
      RECT 0.000 71.925 0.070 71.995 ;
    END
  END wd_in[49]
  PIN wd_in[50]
    DIRECTION INPUT ;
    USE SIGNAL ;
    SHAPE ABUTMENT ;
    PORT
      LAYER metal3 ;
      RECT 0.000 72.205 0.070 72.275 ;
    END
  END wd_in[50]
  PIN wd_in[51]
    DIRECTION INPUT ;
    USE SIGNAL ;
    SHAPE ABUTMENT ;
    PORT
      LAYER metal3 ;
      RECT 0.000 72.485 0.070 72.555 ;
    END
  END wd_in[51]
  PIN wd_in[52]
    DIRECTION INPUT ;
    USE SIGNAL ;
    SHAPE ABUTMENT ;
    PORT
      LAYER metal3 ;
      RECT 0.000 72.765 0.070 72.835 ;
    END
  END wd_in[52]
  PIN wd_in[53]
    DIRECTION INPUT ;
    USE SIGNAL ;
    SHAPE ABUTMENT ;
    PORT
      LAYER metal3 ;
      RECT 0.000 73.045 0.070 73.115 ;
    END
  END wd_in[53]
  PIN wd_in[54]
    DIRECTION INPUT ;
    USE SIGNAL ;
    SHAPE ABUTMENT ;
    PORT
      LAYER metal3 ;
      RECT 0.000 73.325 0.070 73.395 ;
    END
  END wd_in[54]
  PIN wd_in[55]
    DIRECTION INPUT ;
    USE SIGNAL ;
    SHAPE ABUTMENT ;
    PORT
      LAYER metal3 ;
      RECT 0.000 73.605 0.070 73.675 ;
    END
  END wd_in[55]
  PIN wd_in[56]
    DIRECTION INPUT ;
    USE SIGNAL ;
    SHAPE ABUTMENT ;
    PORT
      LAYER metal3 ;
      RECT 0.000 73.885 0.070 73.955 ;
    END
  END wd_in[56]
  PIN wd_in[57]
    DIRECTION INPUT ;
    USE SIGNAL ;
    SHAPE ABUTMENT ;
    PORT
      LAYER metal3 ;
      RECT 0.000 74.165 0.070 74.235 ;
    END
  END wd_in[57]
  PIN wd_in[58]
    DIRECTION INPUT ;
    USE SIGNAL ;
    SHAPE ABUTMENT ;
    PORT
      LAYER metal3 ;
      RECT 0.000 74.445 0.070 74.515 ;
    END
  END wd_in[58]
  PIN wd_in[59]
    DIRECTION INPUT ;
    USE SIGNAL ;
    SHAPE ABUTMENT ;
    PORT
      LAYER metal3 ;
      RECT 0.000 74.725 0.070 74.795 ;
    END
  END wd_in[59]
  PIN wd_in[60]
    DIRECTION INPUT ;
    USE SIGNAL ;
    SHAPE ABUTMENT ;
    PORT
      LAYER metal3 ;
      RECT 0.000 75.005 0.070 75.075 ;
    END
  END wd_in[60]
  PIN wd_in[61]
    DIRECTION INPUT ;
    USE SIGNAL ;
    SHAPE ABUTMENT ;
    PORT
      LAYER metal3 ;
      RECT 0.000 75.285 0.070 75.355 ;
    END
  END wd_in[61]
  PIN wd_in[62]
    DIRECTION INPUT ;
    USE SIGNAL ;
    SHAPE ABUTMENT ;
    PORT
      LAYER metal3 ;
      RECT 0.000 75.565 0.070 75.635 ;
    END
  END wd_in[62]
  PIN wd_in[63]
    DIRECTION INPUT ;
    USE SIGNAL ;
    SHAPE ABUTMENT ;
    PORT
      LAYER metal3 ;
      RECT 0.000 75.845 0.070 75.915 ;
    END
  END wd_in[63]
  PIN addr_in[0]
    DIRECTION INPUT ;
    USE SIGNAL ;
    SHAPE ABUTMENT ;
    PORT
      LAYER metal3 ;
      RECT 0.000 85.925 0.070 85.995 ;
    END
  END addr_in[0]
  PIN addr_in[1]
    DIRECTION INPUT ;
    USE SIGNAL ;
    SHAPE ABUTMENT ;
    PORT
      LAYER metal3 ;
      RECT 0.000 86.205 0.070 86.275 ;
    END
  END addr_in[1]
  PIN addr_in[2]
    DIRECTION INPUT ;
    USE SIGNAL ;
    SHAPE ABUTMENT ;
    PORT
      LAYER metal3 ;
      RECT 0.000 86.485 0.070 86.555 ;
    END
  END addr_in[2]
  PIN addr_in[3]
    DIRECTION INPUT ;
    USE SIGNAL ;
    SHAPE ABUTMENT ;
    PORT
      LAYER metal3 ;
      RECT 0.000 86.765 0.070 86.835 ;
    END
  END addr_in[3]
  PIN addr_in[4]
    DIRECTION INPUT ;
    USE SIGNAL ;
    SHAPE ABUTMENT ;
    PORT
      LAYER metal3 ;
      RECT 0.000 87.045 0.070 87.115 ;
    END
  END addr_in[4]
  PIN addr_in[5]
    DIRECTION INPUT ;
    USE SIGNAL ;
    SHAPE ABUTMENT ;
    PORT
      LAYER metal3 ;
      RECT 0.000 87.325 0.070 87.395 ;
    END
  END addr_in[5]
  PIN we_in
    DIRECTION INPUT ;
    USE SIGNAL ;
    SHAPE ABUTMENT ;
    PORT
      LAYER metal3 ;
      RECT 0.000 97.405 0.070 97.475 ;
    END
  END we_in
  PIN ce_in
    DIRECTION INPUT ;
    USE SIGNAL ;
    SHAPE ABUTMENT ;
    PORT
      LAYER metal3 ;
      RECT 0.000 97.685 0.070 97.755 ;
    END
  END ce_in
  PIN clk
    DIRECTION INPUT ;
    USE SIGNAL ;
    SHAPE ABUTMENT ;
    PORT
      LAYER metal3 ;
      RECT 0.000 97.965 0.070 98.035 ;
    END
  END clk
  PIN VSS
    DIRECTION INOUT ;
    USE GROUND ;
    PORT
      LAYER metal4 ;
      RECT 2.660 2.800 2.940 99.400 ;
      RECT 7.140 2.800 7.420 99.400 ;
      RECT 11.620 2.800 11.900 99.400 ;
      RECT 16.100 2.800 16.380 99.400 ;
      RECT 20.580 2.800 20.860 99.400 ;
      RECT 25.060 2.800 25.340 99.400 ;
      RECT 29.540 2.800 29.820 99.400 ;
      RECT 34.020 2.800 34.300 99.400 ;
      RECT 38.500 2.800 38.780 99.400 ;
      RECT 42.980 2.800 43.260 99.400 ;
      RECT 47.460 2.800 47.740 99.400 ;
      RECT 51.940 2.800 52.220 99.400 ;
    END
  END VSS
  PIN VDD
    DIRECTION INOUT ;
    USE POWER ;
    PORT
      LAYER metal4 ;
      RECT 4.900 2.800 5.180 99.400 ;
      RECT 9.380 2.800 9.660 99.400 ;
      RECT 13.860 2.800 14.140 99.400 ;
      RECT 18.340 2.800 18.620 99.400 ;
      RECT 22.820 2.800 23.100 99.400 ;
      RECT 27.300 2.800 27.580 99.400 ;
      RECT 31.780 2.800 32.060 99.400 ;
      RECT 36.260 2.800 36.540 99.400 ;
      RECT 40.740 2.800 41.020 99.400 ;
      RECT 45.220 2.800 45.500 99.400 ;
      RECT 49.700 2.800 49.980 99.400 ;
    END
  END VDD
  OBS
    LAYER metal1 ;
    RECT 0 0 56.050 102.200 ;
    LAYER metal2 ;
    RECT 0 0 56.050 102.200 ;
    LAYER metal3 ;
    RECT 0.070 0 56.050 102.200 ;
    RECT 0 0.000 0.070 2.765 ;
    RECT 0 2.835 0.070 3.045 ;
    RECT 0 3.115 0.070 3.325 ;
    RECT 0 3.395 0.070 3.605 ;
    RECT 0 3.675 0.070 3.885 ;
    RECT 0 3.955 0.070 4.165 ;
    RECT 0 4.235 0.070 4.445 ;
    RECT 0 4.515 0.070 4.725 ;
    RECT 0 4.795 0.070 5.005 ;
    RECT 0 5.075 0.070 5.285 ;
    RECT 0 5.355 0.070 5.565 ;
    RECT 0 5.635 0.070 5.845 ;
    RECT 0 5.915 0.070 6.125 ;
    RECT 0 6.195 0.070 6.405 ;
    RECT 0 6.475 0.070 6.685 ;
    RECT 0 6.755 0.070 6.965 ;
    RECT 0 7.035 0.070 7.245 ;
    RECT 0 7.315 0.070 7.525 ;
    RECT 0 7.595 0.070 7.805 ;
    RECT 0 7.875 0.070 8.085 ;
    RECT 0 8.155 0.070 8.365 ;
    RECT 0 8.435 0.070 8.645 ;
    RECT 0 8.715 0.070 8.925 ;
    RECT 0 8.995 0.070 9.205 ;
    RECT 0 9.275 0.070 9.485 ;
    RECT 0 9.555 0.070 9.765 ;
    RECT 0 9.835 0.070 10.045 ;
    RECT 0 10.115 0.070 10.325 ;
    RECT 0 10.395 0.070 10.605 ;
    RECT 0 10.675 0.070 10.885 ;
    RECT 0 10.955 0.070 11.165 ;
    RECT 0 11.235 0.070 11.445 ;
    RECT 0 11.515 0.070 11.725 ;
    RECT 0 11.795 0.070 12.005 ;
    RECT 0 12.075 0.070 12.285 ;
    RECT 0 12.355 0.070 12.565 ;
    RECT 0 12.635 0.070 12.845 ;
    RECT 0 12.915 0.070 13.125 ;
    RECT 0 13.195 0.070 13.405 ;
    RECT 0 13.475 0.070 13.685 ;
    RECT 0 13.755 0.070 13.965 ;
    RECT 0 14.035 0.070 14.245 ;
    RECT 0 14.315 0.070 14.525 ;
    RECT 0 14.595 0.070 14.805 ;
    RECT 0 14.875 0.070 15.085 ;
    RECT 0 15.155 0.070 15.365 ;
    RECT 0 15.435 0.070 15.645 ;
    RECT 0 15.715 0.070 15.925 ;
    RECT 0 15.995 0.070 16.205 ;
    RECT 0 16.275 0.070 16.485 ;
    RECT 0 16.555 0.070 16.765 ;
    RECT 0 16.835 0.070 17.045 ;
    RECT 0 17.115 0.070 17.325 ;
    RECT 0 17.395 0.070 17.605 ;
    RECT 0 17.675 0.070 17.885 ;
    RECT 0 17.955 0.070 18.165 ;
    RECT 0 18.235 0.070 18.445 ;
    RECT 0 18.515 0.070 18.725 ;
    RECT 0 18.795 0.070 19.005 ;
    RECT 0 19.075 0.070 19.285 ;
    RECT 0 19.355 0.070 19.565 ;
    RECT 0 19.635 0.070 19.845 ;
    RECT 0 19.915 0.070 20.125 ;
    RECT 0 20.195 0.070 20.405 ;
    RECT 0 20.475 0.070 30.485 ;
    RECT 0 30.555 0.070 30.765 ;
    RECT 0 30.835 0.070 31.045 ;
    RECT 0 31.115 0.070 31.325 ;
    RECT 0 31.395 0.070 31.605 ;
    RECT 0 31.675 0.070 31.885 ;
    RECT 0 31.955 0.070 32.165 ;
    RECT 0 32.235 0.070 32.445 ;
    RECT 0 32.515 0.070 32.725 ;
    RECT 0 32.795 0.070 33.005 ;
    RECT 0 33.075 0.070 33.285 ;
    RECT 0 33.355 0.070 33.565 ;
    RECT 0 33.635 0.070 33.845 ;
    RECT 0 33.915 0.070 34.125 ;
    RECT 0 34.195 0.070 34.405 ;
    RECT 0 34.475 0.070 34.685 ;
    RECT 0 34.755 0.070 34.965 ;
    RECT 0 35.035 0.070 35.245 ;
    RECT 0 35.315 0.070 35.525 ;
    RECT 0 35.595 0.070 35.805 ;
    RECT 0 35.875 0.070 36.085 ;
    RECT 0 36.155 0.070 36.365 ;
    RECT 0 36.435 0.070 36.645 ;
    RECT 0 36.715 0.070 36.925 ;
    RECT 0 36.995 0.070 37.205 ;
    RECT 0 37.275 0.070 37.485 ;
    RECT 0 37.555 0.070 37.765 ;
    RECT 0 37.835 0.070 38.045 ;
    RECT 0 38.115 0.070 38.325 ;
    RECT 0 38.395 0.070 38.605 ;
    RECT 0 38.675 0.070 38.885 ;
    RECT 0 38.955 0.070 39.165 ;
    RECT 0 39.235 0.070 39.445 ;
    RECT 0 39.515 0.070 39.725 ;
    RECT 0 39.795 0.070 40.005 ;
    RECT 0 40.075 0.070 40.285 ;
    RECT 0 40.355 0.070 40.565 ;
    RECT 0 40.635 0.070 40.845 ;
    RECT 0 40.915 0.070 41.125 ;
    RECT 0 41.195 0.070 41.405 ;
    RECT 0 41.475 0.070 41.685 ;
    RECT 0 41.755 0.070 41.965 ;
    RECT 0 42.035 0.070 42.245 ;
    RECT 0 42.315 0.070 42.525 ;
    RECT 0 42.595 0.070 42.805 ;
    RECT 0 42.875 0.070 43.085 ;
    RECT 0 43.155 0.070 43.365 ;
    RECT 0 43.435 0.070 43.645 ;
    RECT 0 43.715 0.070 43.925 ;
    RECT 0 43.995 0.070 44.205 ;
    RECT 0 44.275 0.070 44.485 ;
    RECT 0 44.555 0.070 44.765 ;
    RECT 0 44.835 0.070 45.045 ;
    RECT 0 45.115 0.070 45.325 ;
    RECT 0 45.395 0.070 45.605 ;
    RECT 0 45.675 0.070 45.885 ;
    RECT 0 45.955 0.070 46.165 ;
    RECT 0 46.235 0.070 46.445 ;
    RECT 0 46.515 0.070 46.725 ;
    RECT 0 46.795 0.070 47.005 ;
    RECT 0 47.075 0.070 47.285 ;
    RECT 0 47.355 0.070 47.565 ;
    RECT 0 47.635 0.070 47.845 ;
    RECT 0 47.915 0.070 48.125 ;
    RECT 0 48.195 0.070 58.205 ;
    RECT 0 58.275 0.070 58.485 ;
    RECT 0 58.555 0.070 58.765 ;
    RECT 0 58.835 0.070 59.045 ;
    RECT 0 59.115 0.070 59.325 ;
    RECT 0 59.395 0.070 59.605 ;
    RECT 0 59.675 0.070 59.885 ;
    RECT 0 59.955 0.070 60.165 ;
    RECT 0 60.235 0.070 60.445 ;
    RECT 0 60.515 0.070 60.725 ;
    RECT 0 60.795 0.070 61.005 ;
    RECT 0 61.075 0.070 61.285 ;
    RECT 0 61.355 0.070 61.565 ;
    RECT 0 61.635 0.070 61.845 ;
    RECT 0 61.915 0.070 62.125 ;
    RECT 0 62.195 0.070 62.405 ;
    RECT 0 62.475 0.070 62.685 ;
    RECT 0 62.755 0.070 62.965 ;
    RECT 0 63.035 0.070 63.245 ;
    RECT 0 63.315 0.070 63.525 ;
    RECT 0 63.595 0.070 63.805 ;
    RECT 0 63.875 0.070 64.085 ;
    RECT 0 64.155 0.070 64.365 ;
    RECT 0 64.435 0.070 64.645 ;
    RECT 0 64.715 0.070 64.925 ;
    RECT 0 64.995 0.070 65.205 ;
    RECT 0 65.275 0.070 65.485 ;
    RECT 0 65.555 0.070 65.765 ;
    RECT 0 65.835 0.070 66.045 ;
    RECT 0 66.115 0.070 66.325 ;
    RECT 0 66.395 0.070 66.605 ;
    RECT 0 66.675 0.070 66.885 ;
    RECT 0 66.955 0.070 67.165 ;
    RECT 0 67.235 0.070 67.445 ;
    RECT 0 67.515 0.070 67.725 ;
    RECT 0 67.795 0.070 68.005 ;
    RECT 0 68.075 0.070 68.285 ;
    RECT 0 68.355 0.070 68.565 ;
    RECT 0 68.635 0.070 68.845 ;
    RECT 0 68.915 0.070 69.125 ;
    RECT 0 69.195 0.070 69.405 ;
    RECT 0 69.475 0.070 69.685 ;
    RECT 0 69.755 0.070 69.965 ;
    RECT 0 70.035 0.070 70.245 ;
    RECT 0 70.315 0.070 70.525 ;
    RECT 0 70.595 0.070 70.805 ;
    RECT 0 70.875 0.070 71.085 ;
    RECT 0 71.155 0.070 71.365 ;
    RECT 0 71.435 0.070 71.645 ;
    RECT 0 71.715 0.070 71.925 ;
    RECT 0 71.995 0.070 72.205 ;
    RECT 0 72.275 0.070 72.485 ;
    RECT 0 72.555 0.070 72.765 ;
    RECT 0 72.835 0.070 73.045 ;
    RECT 0 73.115 0.070 73.325 ;
    RECT 0 73.395 0.070 73.605 ;
    RECT 0 73.675 0.070 73.885 ;
    RECT 0 73.955 0.070 74.165 ;
    RECT 0 74.235 0.070 74.445 ;
    RECT 0 74.515 0.070 74.725 ;
    RECT 0 74.795 0.070 75.005 ;
    RECT 0 75.075 0.070 75.285 ;
    RECT 0 75.355 0.070 75.565 ;
    RECT 0 75.635 0.070 75.845 ;
    RECT 0 75.915 0.070 85.925 ;
    RECT 0 85.995 0.070 86.205 ;
    RECT 0 86.275 0.070 86.485 ;
    RECT 0 86.555 0.070 86.765 ;
    RECT 0 86.835 0.070 87.045 ;
    RECT 0 87.115 0.070 87.325 ;
    RECT 0 87.395 0.070 97.405 ;
    RECT 0 97.475 0.070 97.685 ;
    RECT 0 97.755 0.070 97.965 ;
    RECT 0 98.035 0.070 102.200 ;
    LAYER metal4 ;
    RECT 0 0 56.050 2.800 ;
    RECT 0 99.400 56.050 102.200 ;
    RECT 0.000 2.800 2.660 99.400 ;
    RECT 2.940 2.800 4.900 99.400 ;
    RECT 5.180 2.800 7.140 99.400 ;
    RECT 7.420 2.800 9.380 99.400 ;
    RECT 9.660 2.800 11.620 99.400 ;
    RECT 11.900 2.800 13.860 99.400 ;
    RECT 14.140 2.800 16.100 99.400 ;
    RECT 16.380 2.800 18.340 99.400 ;
    RECT 18.620 2.800 20.580 99.400 ;
    RECT 20.860 2.800 22.820 99.400 ;
    RECT 23.100 2.800 25.060 99.400 ;
    RECT 25.340 2.800 27.300 99.400 ;
    RECT 27.580 2.800 29.540 99.400 ;
    RECT 29.820 2.800 31.780 99.400 ;
    RECT 32.060 2.800 34.020 99.400 ;
    RECT 34.300 2.800 36.260 99.400 ;
    RECT 36.540 2.800 38.500 99.400 ;
    RECT 38.780 2.800 40.740 99.400 ;
    RECT 41.020 2.800 42.980 99.400 ;
    RECT 43.260 2.800 45.220 99.400 ;
    RECT 45.500 2.800 47.460 99.400 ;
    RECT 47.740 2.800 49.700 99.400 ;
    RECT 49.980 2.800 51.940 99.400 ;
    RECT 52.220 2.800 56.050 99.400 ;
    LAYER OVERLAP ;
    RECT 0 0 56.050 102.200 ;
  END
END sram_sp_64x64

END LIBRARY
